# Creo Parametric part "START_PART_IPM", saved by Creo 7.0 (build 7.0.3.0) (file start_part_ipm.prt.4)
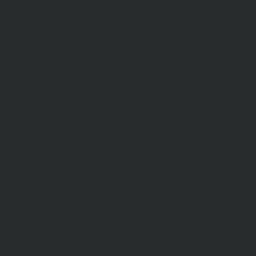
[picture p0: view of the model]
Units: IPM (mmkgsecC); MM, KILOGRAM, SECS
Materials in the file: OCEL, HLINIK, MED, MOSADZ, PVC, SEDA_LIATINA, TEFLON, ZINOK

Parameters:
  PTC_MATERIAL_NAME = "OCEL"
  PRO_UNIT_SYS = "IPM (mmkgsecC)"

Other parameters: HMOTNOST, HUSTOTA

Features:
  1. datum plane "BOKORYS"
  2. datum plane "PODORYS"
  3. datum plane "NARYS"
  4. coordinate system

Other named items: KSYS

Layers: 01_STD_KSYS, 02_STD_ROVINY, 03_KSYS, 04_ROVINY, 05_OSI, 06_BODY, 07_KRIVKY, 08_PLOCHY, 09_QUILTY, 10_DIERY, 11_ZAVITY, 12_KOZMETICKE_PRVKY, 13_KOPIROVANA_GEOM, 14_EXT_KOPIROVANA_GEOM, 15_SKELETONY, XSEC_ROVINY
